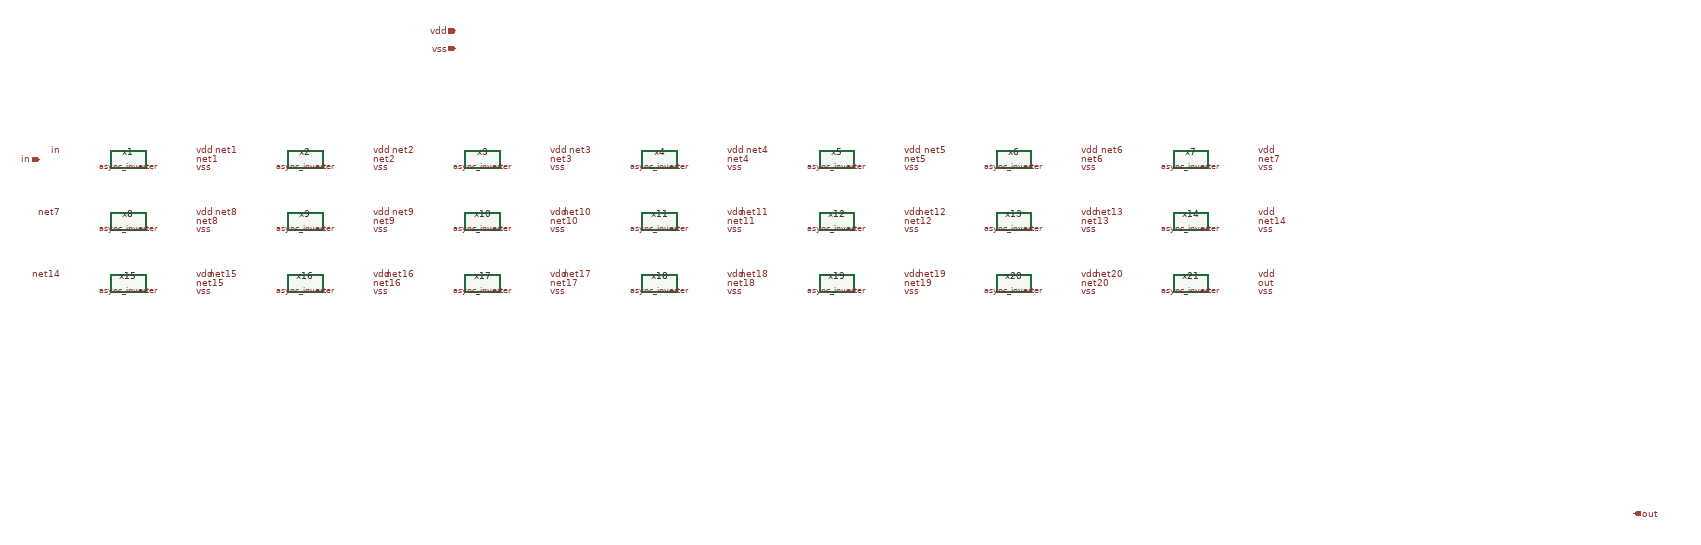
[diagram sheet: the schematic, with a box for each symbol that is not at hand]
v {xschem version=3.4.8RC file_version=1.3}
G {}
K {}
V {}
S {}
F {}
E {}
C {ipin.sym} -1600 -400 0 0 {name=p_in lab=in}
C {iopin.sym} -660 -690 0 0 {name=p_vdd lab=vdd}
C {iopin.sym} -660 -650 0 0 {name=p_vss lab=vss}
C {opin.sym} 2000 400 0 0 {name=p_out lab=out}
C {sar_adc/blocks/async_sar/async_inverter.sym} -1400 -400 0 0 {name=x1}
C {lab_wire.sym} -1550 -420 0 0 {name=l_x1_in lab=in}
C {lab_wire.sym} -1250 -400 2 0 {name=l_x1_out lab=net1}
C {lab_wire.sym} -1250 -420 2 0 {name=l_x1_vdd lab=vdd}
C {lab_wire.sym} -1250 -380 2 0 {name=l_x1_vss lab=vss}
C {sar_adc/blocks/async_sar/async_inverter.sym} -1000 -400 0 0 {name=x2}
C {lab_wire.sym} -1150 -420 0 0 {name=l_x2_in lab=net1}
C {lab_wire.sym} -850 -400 2 0 {name=l_x2_out lab=net2}
C {lab_wire.sym} -850 -420 2 0 {name=l_x2_vdd lab=vdd}
C {lab_wire.sym} -850 -380 2 0 {name=l_x2_vss lab=vss}
C {sar_adc/blocks/async_sar/async_inverter.sym} -600 -400 0 0 {name=x3}
C {lab_wire.sym} -750 -420 0 0 {name=l_x3_in lab=net2}
C {lab_wire.sym} -450 -400 2 0 {name=l_x3_out lab=net3}
C {lab_wire.sym} -450 -420 2 0 {name=l_x3_vdd lab=vdd}
C {lab_wire.sym} -450 -380 2 0 {name=l_x3_vss lab=vss}
C {sar_adc/blocks/async_sar/async_inverter.sym} -200 -400 0 0 {name=x4}
C {lab_wire.sym} -350 -420 0 0 {name=l_x4_in lab=net3}
C {lab_wire.sym} -50 -400 2 0 {name=l_x4_out lab=net4}
C {lab_wire.sym} -50 -420 2 0 {name=l_x4_vdd lab=vdd}
C {lab_wire.sym} -50 -380 2 0 {name=l_x4_vss lab=vss}
C {sar_adc/blocks/async_sar/async_inverter.sym} 200 -400 0 0 {name=x5}
C {lab_wire.sym} 50 -420 0 0 {name=l_x5_in lab=net4}
C {lab_wire.sym} 350 -400 2 0 {name=l_x5_out lab=net5}
C {lab_wire.sym} 350 -420 2 0 {name=l_x5_vdd lab=vdd}
C {lab_wire.sym} 350 -380 2 0 {name=l_x5_vss lab=vss}
C {sar_adc/blocks/async_sar/async_inverter.sym} 600 -400 0 0 {name=x6}
C {lab_wire.sym} 450 -420 0 0 {name=l_x6_in lab=net5}
C {lab_wire.sym} 750 -400 2 0 {name=l_x6_out lab=net6}
C {lab_wire.sym} 750 -420 2 0 {name=l_x6_vdd lab=vdd}
C {lab_wire.sym} 750 -380 2 0 {name=l_x6_vss lab=vss}
C {sar_adc/blocks/async_sar/async_inverter.sym} 1000 -400 0 0 {name=x7}
C {lab_wire.sym} 850 -420 0 0 {name=l_x7_in lab=net6}
C {lab_wire.sym} 1150 -400 2 0 {name=l_x7_out lab=net7}
C {lab_wire.sym} 1150 -420 2 0 {name=l_x7_vdd lab=vdd}
C {lab_wire.sym} 1150 -380 2 0 {name=l_x7_vss lab=vss}
C {sar_adc/blocks/async_sar/async_inverter.sym} -1400 -260 0 0 {name=x8}
C {lab_wire.sym} -1550 -280 0 0 {name=l_x8_in lab=net7}
C {lab_wire.sym} -1250 -260 2 0 {name=l_x8_out lab=net8}
C {lab_wire.sym} -1250 -280 2 0 {name=l_x8_vdd lab=vdd}
C {lab_wire.sym} -1250 -240 2 0 {name=l_x8_vss lab=vss}
C {sar_adc/blocks/async_sar/async_inverter.sym} -1000 -260 0 0 {name=x9}
C {lab_wire.sym} -1150 -280 0 0 {name=l_x9_in lab=net8}
C {lab_wire.sym} -850 -260 2 0 {name=l_x9_out lab=net9}
C {lab_wire.sym} -850 -280 2 0 {name=l_x9_vdd lab=vdd}
C {lab_wire.sym} -850 -240 2 0 {name=l_x9_vss lab=vss}
C {sar_adc/blocks/async_sar/async_inverter.sym} -600 -260 0 0 {name=x10}
C {lab_wire.sym} -750 -280 0 0 {name=l_x10_in lab=net9}
C {lab_wire.sym} -450 -260 2 0 {name=l_x10_out lab=net10}
C {lab_wire.sym} -450 -280 2 0 {name=l_x10_vdd lab=vdd}
C {lab_wire.sym} -450 -240 2 0 {name=l_x10_vss lab=vss}
C {sar_adc/blocks/async_sar/async_inverter.sym} -200 -260 0 0 {name=x11}
C {lab_wire.sym} -350 -280 0 0 {name=l_x11_in lab=net10}
C {lab_wire.sym} -50 -260 2 0 {name=l_x11_out lab=net11}
C {lab_wire.sym} -50 -280 2 0 {name=l_x11_vdd lab=vdd}
C {lab_wire.sym} -50 -240 2 0 {name=l_x11_vss lab=vss}
C {sar_adc/blocks/async_sar/async_inverter.sym} 200 -260 0 0 {name=x12}
C {lab_wire.sym} 50 -280 0 0 {name=l_x12_in lab=net11}
C {lab_wire.sym} 350 -260 2 0 {name=l_x12_out lab=net12}
C {lab_wire.sym} 350 -280 2 0 {name=l_x12_vdd lab=vdd}
C {lab_wire.sym} 350 -240 2 0 {name=l_x12_vss lab=vss}
C {sar_adc/blocks/async_sar/async_inverter.sym} 600 -260 0 0 {name=x13}
C {lab_wire.sym} 450 -280 0 0 {name=l_x13_in lab=net12}
C {lab_wire.sym} 750 -260 2 0 {name=l_x13_out lab=net13}
C {lab_wire.sym} 750 -280 2 0 {name=l_x13_vdd lab=vdd}
C {lab_wire.sym} 750 -240 2 0 {name=l_x13_vss lab=vss}
C {sar_adc/blocks/async_sar/async_inverter.sym} 1000 -260 0 0 {name=x14}
C {lab_wire.sym} 850 -280 0 0 {name=l_x14_in lab=net13}
C {lab_wire.sym} 1150 -260 2 0 {name=l_x14_out lab=net14}
C {lab_wire.sym} 1150 -280 2 0 {name=l_x14_vdd lab=vdd}
C {lab_wire.sym} 1150 -240 2 0 {name=l_x14_vss lab=vss}
C {sar_adc/blocks/async_sar/async_inverter.sym} -1400 -120 0 0 {name=x15}
C {lab_wire.sym} -1550 -140 0 0 {name=l_x15_in lab=net14}
C {lab_wire.sym} -1250 -120 2 0 {name=l_x15_out lab=net15}
C {lab_wire.sym} -1250 -140 2 0 {name=l_x15_vdd lab=vdd}
C {lab_wire.sym} -1250 -100 2 0 {name=l_x15_vss lab=vss}
C {sar_adc/blocks/async_sar/async_inverter.sym} -1000 -120 0 0 {name=x16}
C {lab_wire.sym} -1150 -140 0 0 {name=l_x16_in lab=net15}
C {lab_wire.sym} -850 -120 2 0 {name=l_x16_out lab=net16}
C {lab_wire.sym} -850 -140 2 0 {name=l_x16_vdd lab=vdd}
C {lab_wire.sym} -850 -100 2 0 {name=l_x16_vss lab=vss}
C {sar_adc/blocks/async_sar/async_inverter.sym} -600 -120 0 0 {name=x17}
C {lab_wire.sym} -750 -140 0 0 {name=l_x17_in lab=net16}
C {lab_wire.sym} -450 -120 2 0 {name=l_x17_out lab=net17}
C {lab_wire.sym} -450 -140 2 0 {name=l_x17_vdd lab=vdd}
C {lab_wire.sym} -450 -100 2 0 {name=l_x17_vss lab=vss}
C {sar_adc/blocks/async_sar/async_inverter.sym} -200 -120 0 0 {name=x18}
C {lab_wire.sym} -350 -140 0 0 {name=l_x18_in lab=net17}
C {lab_wire.sym} -50 -120 2 0 {name=l_x18_out lab=net18}
C {lab_wire.sym} -50 -140 2 0 {name=l_x18_vdd lab=vdd}
C {lab_wire.sym} -50 -100 2 0 {name=l_x18_vss lab=vss}
C {sar_adc/blocks/async_sar/async_inverter.sym} 200 -120 0 0 {name=x19}
C {lab_wire.sym} 50 -140 0 0 {name=l_x19_in lab=net18}
C {lab_wire.sym} 350 -120 2 0 {name=l_x19_out lab=net19}
C {lab_wire.sym} 350 -140 2 0 {name=l_x19_vdd lab=vdd}
C {lab_wire.sym} 350 -100 2 0 {name=l_x19_vss lab=vss}
C {sar_adc/blocks/async_sar/async_inverter.sym} 600 -120 0 0 {name=x20}
C {lab_wire.sym} 450 -140 0 0 {name=l_x20_in lab=net19}
C {lab_wire.sym} 750 -120 2 0 {name=l_x20_out lab=net20}
C {lab_wire.sym} 750 -140 2 0 {name=l_x20_vdd lab=vdd}
C {lab_wire.sym} 750 -100 2 0 {name=l_x20_vss lab=vss}
C {sar_adc/blocks/async_sar/async_inverter.sym} 1000 -120 0 0 {name=x21}
C {lab_wire.sym} 850 -140 0 0 {name=l_x21_in lab=net20}
C {lab_wire.sym} 1150 -120 2 0 {name=l_x21_out lab=out}
C {lab_wire.sym} 1150 -140 2 0 {name=l_x21_vdd lab=vdd}
C {lab_wire.sym} 1150 -100 2 0 {name=l_x21_vss lab=vss}
